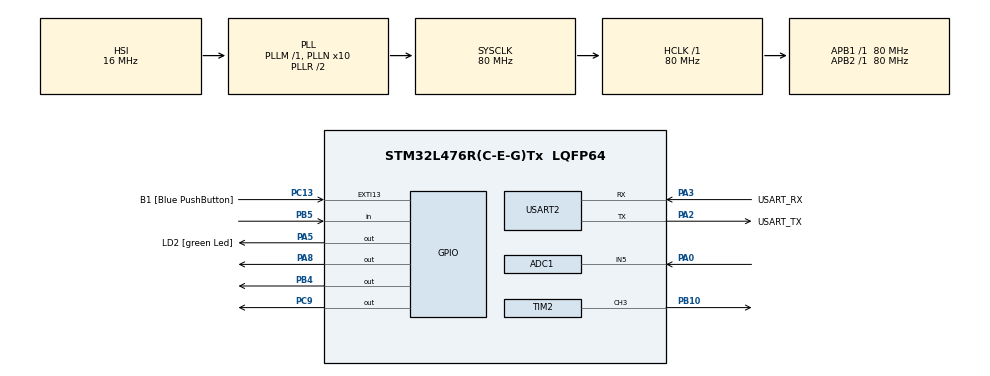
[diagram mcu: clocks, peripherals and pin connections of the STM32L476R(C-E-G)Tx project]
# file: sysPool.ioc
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ADC1.Channel-1\#ChannelRegularConversion=ADC_CHANNEL_5
ADC1.NbrOfConversionFlag=1
ADC1.OffsetNumber-1\#ChannelRegularConversion=ADC_OFFSET_NONE
ADC1.Rank-1\#ChannelRegularConversion=1
ADC1.SamplingTime-1\#ChannelRegularConversion=ADC_SAMPLETIME_2CYCLES_5
ADC1.master=1
FREERTOS.Tasks01=defaultTask,0,128,StartDefaultTask,Default,NULL,Dynamic,NULL,NULL
Mcu.Family=STM32L4
Mcu.Name=STM32L476R(C-E-G)Tx
Mcu.Package=LQFP64
NVIC.PriorityGroup=NVIC_PRIORITYGROUP_4
PA0.Signal=ADCx_IN5
PA13\ (JTMS-SWDIO).GPIO_Label=TMS
PA13\ (JTMS-SWDIO).Mode=Serial_Wire
PA13\ (JTMS-SWDIO).Signal=SYS_JTMS-SWDIO
PA14\ (JTCK-SWCLK).GPIO_Label=TCK
PA14\ (JTCK-SWCLK).Mode=Serial_Wire
PA14\ (JTCK-SWCLK).Signal=SYS_JTCK-SWCLK
PA2.GPIO_Label=USART_TX
PA2.GPIO_Mode=GPIO_MODE_AF_PP
PA2.GPIO_PuPd=GPIO_NOPULL
PA2.GPIO_Speed=GPIO_SPEED_FREQ_VERY_HIGH
PA2.Mode=Asynchronous
PA2.Signal=USART2_TX
PA3.GPIO_Label=USART_RX
PA3.GPIO_Mode=GPIO_MODE_AF_PP
PA3.GPIO_PuPd=GPIO_NOPULL
PA3.GPIO_Speed=GPIO_SPEED_FREQ_VERY_HIGH
PA3.Mode=Asynchronous
PA3.Signal=USART2_RX
PA5.GPIO_Label=LD2 [green Led]
PA5.GPIO_ModeDefaultOutputPP=GPIO_MODE_OUTPUT_PP
PA5.GPIO_PuPd=GPIO_NOPULL
PA5.GPIO_Speed=GPIO_SPEED_FREQ_LOW
PA5.Signal=GPIO_Output
PA8.Signal=GPIO_Output
PB10.Signal=S_TIM2_CH3
PB3\ (JTDO-TRACESWO).GPIO_Label=SWO
PB3\ (JTDO-TRACESWO).Signal=SYS_JTDO-SWO
PB4\ (NJTRST).Signal=GPIO_Output
PB5.Signal=GPIO_Input
PC13.GPIO_Label=B1 [Blue PushButton]
PC13.GPIO_ModeDefaultEXTI=GPIO_MODE_IT_FALLING
PC13.GPIO_PuPd=GPIO_NOPULL
PC13.Signal=GPXTI13
PC14-OSC32_IN\ (PC14).Mode=LSE-External-Oscillator
PC14-OSC32_IN\ (PC14).Signal=RCC_OSC32_IN
PC15-OSC32_OUT\ (PC15).Mode=LSE-External-Oscillator
PC15-OSC32_OUT\ (PC15).Signal=RCC_OSC32_OUT
PC9.Signal=GPIO_Output
PH0-OSC_IN\ (PH0).Signal=RCC_OSC_IN
PH1-OSC_OUT\ (PH1).Signal=RCC_OSC_OUT
ProjectManager.HeapSize=0x200
ProjectManager.StackSize=0x400
ProjectManager.TargetToolchain=STM32CubeIDE
RCC.ADCFreq_Value=64000000
RCC.AHBFreq_Value=80000000
RCC.APB1Freq_Value=80000000
RCC.APB1TimFreq_Value=80000000
RCC.APB2Freq_Value=80000000
RCC.APB2TimFreq_Value=80000000
RCC.CortexFreq_Value=80000000
RCC.HCLKFreq_Value=80000000
RCC.HSE_VALUE=8000000
RCC.HSI_VALUE=16000000
RCC.MSI_VALUE=4000000
RCC.PLLN=10
RCC.PLLSourceVirtual=RCC_PLLSOURCE_HSI
RCC.PREFETCH_ENABLE=1
RCC.SYSCLKFreq_VALUE=80000000
RCC.SYSCLKSource=RCC_SYSCLKSOURCE_PLLCLK
RCC.USBFreq_Value=64000000
RCC.VCOOutputFreq_Value=160000000
SH.ADCx_IN5.0=ADC1_IN5,IN5-Single-Ended
SH.S_TIM2_CH3.0=TIM2_CH3,PWM Generation3 CH3
TIM2.Channel-PWM\ Generation3\ CH3=TIM_CHANNEL_3
USART2.VirtualMode-Asynchronous=VM_ASYNC
VP_FREERTOS_VS_CMSIS_V1.Mode=CMSIS_V1
board=NUCLEO-L476RG

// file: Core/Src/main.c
/* USER CODE BEGIN Header */
/**
  **
  * @file           : main.c
  * @brief          : Main program body
  **
  * @attention
  *
  * Copyright (c) 2024 STMicroelectronics.
  * All rights reserved.
  *
  * This software is licensed under terms that can be found in the LICENSE file
  * in the root directory of this software component.
  * If no LICENSE file comes with this software, it is provided AS-IS.
  *s
  **
  */
/* USER CODE END Header */
#include "main.h"
#include "cmsis_os.h"

/* USER CODE BEGIN Includes */
#define STDOUT_FILENO 1
#define STDERR_FILENO 2
/* Private define ------------------------------------------------------------*/

#define TRIGGER_PIN GPIO_PIN_4  // PB4
#define ECHO_PIN GPIO_PIN_5     // PB5
#define LED_PA8 GPIO_PIN_8
#define LED_PA9 GPIO_PIN_9
#define BUZZER GPIO_PIN_10
#define BUTTON GPIO_PIN_10
#define POTENTIOMETER_CHANNEL ADC_CHANNEL_5
#define RX_BUFFER_SIZE 64

/* USER CODE END Includes */

ADC_HandleTypeDef hadc1;

TIM_HandleTypeDef htim2;

UART_HandleTypeDef huart2;

osThreadId defaultTaskHandle;
/* USER CODE BEGIN PV */
int ledState1 = 0;
int previousButtonState1 = 1;
int ledState2 = 0;
int blinking = 0;
uint32_t duration = 0;
uint32_t adcValue = 0;
uint32_t pwmDutyCycle = 0;
int alertaAtivo = 0;
int sistemaHabilitado = 0;

/* Private variables ---------------------------------------------------------*/
float distInCm = 0;

/* USER CODE END PV */

void SystemClock_Config(void);
static void MX_GPIO_Init(void);
static void MX_USART2_UART_Init(void);
static void MX_ADC1_Init(void);
static void MX_TIM2_Init(void);
void StartDefaultTask(void const * argument);
void buttonTaskFcn(void * argument);
void sensorTaskFcn(void * argument);
void potentiometerTaskFcn(void * argument);
void uartCommandTask(void * argument);

int main(void)
{

  /* MCU Configuration--------------------------------------------------------*/

  /* Reset of all peripherals, Initializes the Flash interface and the Systick. */
  HAL_Init();

  /* Configure the system clock */
  SystemClock_Config();

  /* Initialize all configured peripherals */
  MX_GPIO_Init();
  MX_USART2_UART_Init();
  MX_ADC1_Init();
  MX_TIM2_Init();
  /* USER CODE BEGIN 2 */
  HAL_ADC_Start_IT(&hadc1);

  HAL_TIM_PWM_Start(&htim2, TIM_CHANNEL_3);
  __HAL_TIM_SET_COMPARE(&htim2, TIM_CHANNEL_3, 0);
  /* USER CODE END 2 */

  /* Create the thread(s) */
  /* definition and creation of defaultTask */
  osThreadDef(defaultTask, StartDefaultTask, osPriorityNormal, 0, 128);
  defaultTaskHandle = osThreadCreate(osThread(defaultTask), NULL);

  /* USER CODE BEGIN RTOS_THREADS */
  /* Creating tasks for button, sensor and buzzer */
  xTaskCreate(buttonTaskFcn, "buttonTask", configMINIMAL_STACK_SIZE, NULL, tskIDLE_PRIORITY, NULL);
  xTaskCreate(sensorTaskFcn, "sensorTask", configMINIMAL_STACK_SIZE, NULL, tskIDLE_PRIORITY, NULL);
  xTaskCreate(potentiometerTaskFcn, "potentiometerTask", configMINIMAL_STACK_SIZE, NULL, tskIDLE_PRIORITY, NULL);
  xTaskCreate(uartCommandTask, "uartCommandTask", configMINIMAL_STACK_SIZE, NULL, tskIDLE_PRIORITY, NULL);

  /* USER CODE END RTOS_THREADS */

  /* Start scheduler */
  osKernelStart();

  /* We should never get here as control is now taken by the scheduler */

  /* Infinite loop */
  /* USER CODE BEGIN WHILE */
    while (1)
    {
        // Main loop remains empty as tasks handle operations
    }
    /* USER CODE END WHILE */

}

void SystemClock_Config(void)
{
  RCC_OscInitTypeDef RCC_OscInitStruct = {0};
  RCC_ClkInitTypeDef RCC_ClkInitStruct = {0};

  /** Configure the main internal regulator output voltage
  */
  if (HAL_PWREx_ControlVoltageScaling(PWR_REGULATOR_VOLTAGE_SCALE1) != HAL_OK)
  {
    Error_Handler();
  }

  /** Initializes the RCC Oscillators according to the specified parameters
  * in the RCC_OscInitTypeDef structure.
  */
  RCC_OscInitStruct.OscillatorType = RCC_OSCILLATORTYPE_HSI;
  RCC_OscInitStruct.HSIState = RCC_HSI_ON;
  RCC_OscInitStruct.HSICalibrationValue = RCC_HSICALIBRATION_DEFAULT;
  RCC_OscInitStruct.PLL.PLLState = RCC_PLL_ON;
  RCC_OscInitStruct.PLL.PLLSource = RCC_PLLSOURCE_HSI;
  RCC_OscInitStruct.PLL.PLLM = 1;
  RCC_OscInitStruct.PLL.PLLN = 10;
  RCC_OscInitStruct.PLL.PLLP = RCC_PLLP_DIV7;
  RCC_OscInitStruct.PLL.PLLQ = RCC_PLLQ_DIV2;
  RCC_OscInitStruct.PLL.PLLR = RCC_PLLR_DIV2;
  if (HAL_RCC_OscConfig(&RCC_OscInitStruct) != HAL_OK)
  {
    Error_Handler();
  }

  /** Initializes the CPU, AHB and APB buses clocks
  */
  RCC_ClkInitStruct.ClockType = RCC_CLOCKTYPE_HCLK|RCC_CLOCKTYPE_SYSCLK
                              |RCC_CLOCKTYPE_PCLK1|RCC_CLOCKTYPE_PCLK2;
  RCC_ClkInitStruct.SYSCLKSource = RCC_SYSCLKSOURCE_PLLCLK;
  RCC_ClkInitStruct.AHBCLKDivider = RCC_SYSCLK_DIV1;
  RCC_ClkInitStruct.APB1CLKDivider = RCC_HCLK_DIV1;
  RCC_ClkInitStruct.APB2CLKDivider = RCC_HCLK_DIV1;

  if (HAL_RCC_ClockConfig(&RCC_ClkInitStruct, FLASH_LATENCY_4) != HAL_OK)
  {
    Error_Handler();
  }
}

static void MX_ADC1_Init(void)
{

  ADC_MultiModeTypeDef multimode = {0};
  ADC_ChannelConfTypeDef sConfig = {0};

  /** Common config
  */
  hadc1.Instance = ADC1;
  hadc1.Init.ClockPrescaler = ADC_CLOCK_ASYNC_DIV1;
  hadc1.Init.Resolution = ADC_RESOLUTION_12B;
  hadc1.Init.DataAlign = ADC_DATAALIGN_RIGHT;
  hadc1.Init.ScanConvMode = ADC_SCAN_DISABLE;
  hadc1.Init.EOCSelection = ADC_EOC_SINGLE_CONV;
  hadc1.Init.LowPowerAutoWait = DISABLE;
  hadc1.Init.ContinuousConvMode = DISABLE;
  hadc1.Init.NbrOfConversion = 1;
  hadc1.Init.DiscontinuousConvMode = DISABLE;
  hadc1.Init.ExternalTrigConv = ADC_SOFTWARE_START;
  hadc1.Init.ExternalTrigConvEdge = ADC_EXTERNALTRIGCONVEDGE_NONE;
  hadc1.Init.DMAContinuousRequests = DISABLE;
  hadc1.Init.Overrun = ADC_OVR_DATA_PRESERVED;
  hadc1.Init.OversamplingMode = DISABLE;
  if (HAL_ADC_Init(&hadc1) != HAL_OK)
  {
    Error_Handler();
  }

  /** Configure the ADC multi-mode
  */
  multimode.Mode = ADC_MODE_INDEPENDENT;
  if (HAL_ADCEx_MultiModeConfigChannel(&hadc1, &multimode) != HAL_OK)
  {
    Error_Handler();
  }

  /** Configure Regular Channel
  */
  sConfig.Channel = ADC_CHANNEL_5;
  sConfig.Rank = ADC_REGULAR_RANK_1;
  sConfig.SamplingTime = ADC_SAMPLETIME_2CYCLES_5;
  sConfig.SingleDiff = ADC_SINGLE_ENDED;
  sConfig.OffsetNumber = ADC_OFFSET_NONE;
  sConfig.Offset = 0;
  if (HAL_ADC_ConfigChannel(&hadc1, &sConfig) != HAL_OK)
  {
    Error_Handler();
  }

}

static void MX_TIM2_Init(void)
{

  TIM_MasterConfigTypeDef sMasterConfig = {0};
  TIM_OC_InitTypeDef sConfigOC = {0};

  htim2.Instance = TIM2;
  htim2.Init.Prescaler = 79;
  htim2.Init.CounterMode = TIM_COUNTERMODE_UP;
  htim2.Init.Period = 255;
  htim2.Init.ClockDivision = TIM_CLOCKDIVISION_DIV1;
  htim2.Init.AutoReloadPreload = TIM_AUTORELOAD_PRELOAD_DISABLE;
  if (HAL_TIM_PWM_Init(&htim2) != HAL_OK)
  {
    Error_Handler();
  }
  sMasterConfig.MasterOutputTrigger = TIM_TRGO_RESET;
  sMasterConfig.MasterSlaveMode = TIM_MASTERSLAVEMODE_DISABLE;
  if (HAL_TIMEx_MasterConfigSynchronization(&htim2, &sMasterConfig) != HAL_OK)
  {
    Error_Handler();
  }
  sConfigOC.OCMode = TIM_OCMODE_PWM1;
  sConfigOC.Pulse = 0;
  sConfigOC.OCPolarity = TIM_OCPOLARITY_HIGH;
  sConfigOC.OCFastMode = TIM_OCFAST_DISABLE;
  if (HAL_TIM_PWM_ConfigChannel(&htim2, &sConfigOC, TIM_CHANNEL_3) != HAL_OK)
  {
    Error_Handler();
  }
  HAL_TIM_MspPostInit(&htim2);

}

static void MX_USART2_UART_Init(void)
{

  huart2.Instance = USART2;
  huart2.Init.BaudRate = 115200;
  huart2.Init.WordLength = UART_WORDLENGTH_8B;
  huart2.Init.StopBits = UART_STOPBITS_1;
  huart2.Init.Parity = UART_PARITY_NONE;
  huart2.Init.Mode = UART_MODE_TX_RX;
  huart2.Init.HwFlowCtl = UART_HWCONTROL_NONE;
  huart2.Init.OverSampling = UART_OVERSAMPLING_16;
  huart2.Init.OneBitSampling = UART_ONE_BIT_SAMPLE_DISABLE;
  huart2.AdvancedInit.AdvFeatureInit = UART_ADVFEATURE_NO_INIT;
  if (HAL_UART_Init(&huart2) != HAL_OK)
  {
    Error_Handler();
  }

}

static void MX_GPIO_Init(void)
{
  GPIO_InitTypeDef GPIO_InitStruct = {0};

  /* GPIO Ports Clock Enable */
  __HAL_RCC_GPIOC_CLK_ENABLE();
  __HAL_RCC_GPIOH_CLK_ENABLE();
  __HAL_RCC_GPIOA_CLK_ENABLE();
  __HAL_RCC_GPIOB_CLK_ENABLE();

  /*Configure GPIO pin Output Level */
  HAL_GPIO_WritePin(GPIOA, LD2_Pin|GPIO_PIN_8|GPIO_PIN_9, GPIO_PIN_RESET);

  /*Configure GPIO pin Output Level */
  HAL_GPIO_WritePin(GPIOB, GPIO_PIN_4, GPIO_PIN_RESET);

  /*Configure GPIO pin : B1_Pin */
  GPIO_InitStruct.Pin = B1_Pin;
  GPIO_InitStruct.Mode = GPIO_MODE_IT_FALLING;
  GPIO_InitStruct.Pull = GPIO_NOPULL;
  HAL_GPIO_Init(B1_GPIO_Port, &GPIO_InitStruct);

  /*Configure GPIO pins : LD2_Pin PA8 PA9 */
  GPIO_InitStruct.Pin = LD2_Pin|GPIO_PIN_8|GPIO_PIN_9;
  GPIO_InitStruct.Mode = GPIO_MODE_OUTPUT_PP;
  GPIO_InitStruct.Pull = GPIO_NOPULL;
  GPIO_InitStruct.Speed = GPIO_SPEED_FREQ_LOW;
  HAL_GPIO_Init(GPIOA, &GPIO_InitStruct);

  /*Configure GPIO pin : PA10 */
  GPIO_InitStruct.Pin = GPIO_PIN_10;
  GPIO_InitStruct.Mode = GPIO_MODE_INPUT;
  GPIO_InitStruct.Pull = GPIO_PULLUP;
  HAL_GPIO_Init(GPIOA, &GPIO_InitStruct);

  /*Configure GPIO pin : PB4 */
  GPIO_InitStruct.Pin = GPIO_PIN_4;
  GPIO_InitStruct.Mode = GPIO_MODE_OUTPUT_PP;
  GPIO_InitStruct.Pull = GPIO_NOPULL;
  GPIO_InitStruct.Speed = GPIO_SPEED_FREQ_LOW;
  HAL_GPIO_Init(GPIOB, &GPIO_InitStruct);

  /*Configure GPIO pin : PB5 */
  GPIO_InitStruct.Pin = GPIO_PIN_5;
  GPIO_InitStruct.Mode = GPIO_MODE_INPUT;
  GPIO_InitStruct.Pull = GPIO_NOPULL;
  HAL_GPIO_Init(GPIOB, &GPIO_InitStruct);

}

/* USER CODE BEGIN 4 */
/* USER CODE BEGIN 4 */

/* USER CODE BEGIN 4 */

/* Task para lidar com comandos UART */
void uartCommandTask(void *argument) {
    uint8_t rxBuffer[1];
    for (;;) {
        if (HAL_UART_Receive(&huart2, rxBuffer, sizeof(rxBuffer), HAL_MAX_DELAY) == HAL_OK) {
            char comando = rxBuffer[0];

            switch (comando) {
                case 'O':
                case 'o':
                    HAL_GPIO_WritePin(GPIOA, GPIO_PIN_8, GPIO_PIN_SET);
                    sistemaHabilitado = 1;
                    HAL_UART_Transmit(&huart2, (uint8_t *)"LED PA8 ON e Sensor ON\n\r", strlen("LED PA8 ON e Sensor ON\n\r"), HAL_MAX_DELAY);
                    break;

                case 'F':
                case 'f':
                    HAL_GPIO_WritePin(GPIOA, GPIO_PIN_8, GPIO_PIN_RESET);
                    sistemaHabilitado = 0;
                    HAL_UART_Transmit(&huart2, (uint8_t *)"LED PA8 OFF e Sensor OFF\n\r", strlen("LED PA8 OFF e Sensor OFF\n\r"), HAL_MAX_DELAY);
                    break;

                default:
                    HAL_UART_Transmit(&huart2, (uint8_t *)"Comando invalido\n\r", strlen("Comando invalido\n\r"), HAL_MAX_DELAY);
                    break;
            }
        }
        vTaskDelay(100);
    }
}

/* USER CODE END 4 */

/* Task para o botão e LED PA8 */
void buttonTaskFcn(void * argument) {
    for(;;) {
        int buttonState1 = HAL_GPIO_ReadPin(GPIOA, GPIO_PIN_10);
        if (buttonState1 == 0 && previousButtonState1 == 1) {
            ledState1 = !ledState1;
            HAL_GPIO_WritePin(GPIOA, GPIO_PIN_8, ledState1 ? GPIO_PIN_SET : GPIO_PIN_RESET);

            if (ledState1) {
                sistemaHabilitado = 1;
                HAL_UART_Transmit(&huart2, (uint8_t *)"Sistema habilitado manualmente\n\r", strlen("Sistema habilitado manualmente\n\r"), HAL_MAX_DELAY);
            } else {
                sistemaHabilitado = 0;
                alertaAtivo = 0;
                HAL_GPIO_WritePin(GPIOA, LED_PA9, GPIO_PIN_RESET);
                __HAL_TIM_SET_COMPARE(&htim2, TIM_CHANNEL_3, 0);
                HAL_UART_Transmit(&huart2, (uint8_t *)"Sistema desabilitado manualmente\n\r", strlen("Sistema desabilitado manualmente\n\r"), HAL_MAX_DELAY);
            }
        }
        previousButtonState1 = buttonState1;
        vTaskDelay(100);
    }
}

/* Task para o sensor ultrassônico */
void sensorTaskFcn(void * argument) {
    for(;;) {
        if (sistemaHabilitado) {
            if (alertaAtivo) {
                ledState2 = !ledState2;
                HAL_GPIO_WritePin(GPIOA, LED_PA9, ledState2 ? GPIO_PIN_SET : GPIO_PIN_RESET);

                __HAL_TIM_SET_COMPARE(&htim2, TIM_CHANNEL_3, pwmDutyCycle);
            } else {
                HAL_GPIO_WritePin(GPIOB, TRIGGER_PIN, GPIO_PIN_RESET);
                HAL_Delay(2);
                HAL_GPIO_WritePin(GPIOB, TRIGGER_PIN, GPIO_PIN_SET);
                HAL_Delay(10);
                HAL_GPIO_WritePin(GPIOB, TRIGGER_PIN, GPIO_PIN_RESET);

                while (HAL_GPIO_ReadPin(GPIOB, ECHO_PIN) == GPIO_PIN_RESET);
                uint32_t startTime = HAL_GetTick();
                while (HAL_GPIO_ReadPin(GPIOB, ECHO_PIN) == GPIO_PIN_SET);
                duration = HAL_GetTick() - startTime;

                distInCm = duration * (34300.0 / 2.0);

                if (distInCm < 5.0) {
                    alertaAtivo = 1;
                }
            }
        } else {
            alertaAtivo = 0;
            HAL_GPIO_WritePin(GPIOA, LED_PA9, GPIO_PIN_RESET);
            __HAL_TIM_SET_COMPARE(&htim2, TIM_CHANNEL_3, 0);
        }
        vTaskDelay(100);
    }
}

/* Task para o potenciômetro (ajustando o PWM para controlar o volume do buzzer) */
void potentiometerTaskFcn(void * argument) {
    for(;;) {
        if (sistemaHabilitado) {
            HAL_ADC_Start(&hadc1);
            if (HAL_ADC_PollForConversion(&hadc1, HAL_MAX_DELAY) == HAL_OK) {
                adcValue = HAL_ADC_GetValue(&hadc1);
            }
            HAL_ADC_Stop(&hadc1);

            pwmDutyCycle = (adcValue * 1000) / 4095;
        }
        vTaskDelay(100);
    }
}

/* USER CODE END 4 */

void StartDefaultTask(void const * argument)
{
  for(;;)
  {
    osDelay(1);
  }
}

void HAL_TIM_PeriodElapsedCallback(TIM_HandleTypeDef *htim)
{
  if (htim->Instance == TIM1) {
    HAL_IncTick();
  }
}

void Error_Handler(void)
{
  __disable_irq();
  while (1)
  {
  }
}
